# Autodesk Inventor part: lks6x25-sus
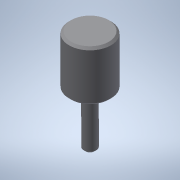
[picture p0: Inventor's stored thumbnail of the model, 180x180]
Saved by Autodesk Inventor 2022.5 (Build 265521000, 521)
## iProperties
Created: 2017-08
Part Number: lks6x25-sus
Material: 一般
Document SubType Name: Modeling
Designer: imaocorp
Density: 1 g/cm^3
Appearance: 既定
Author: imaocorp
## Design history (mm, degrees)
node "lks6x25-sus.x_t1"
node "lks6x25-sus"
node "Base1"
